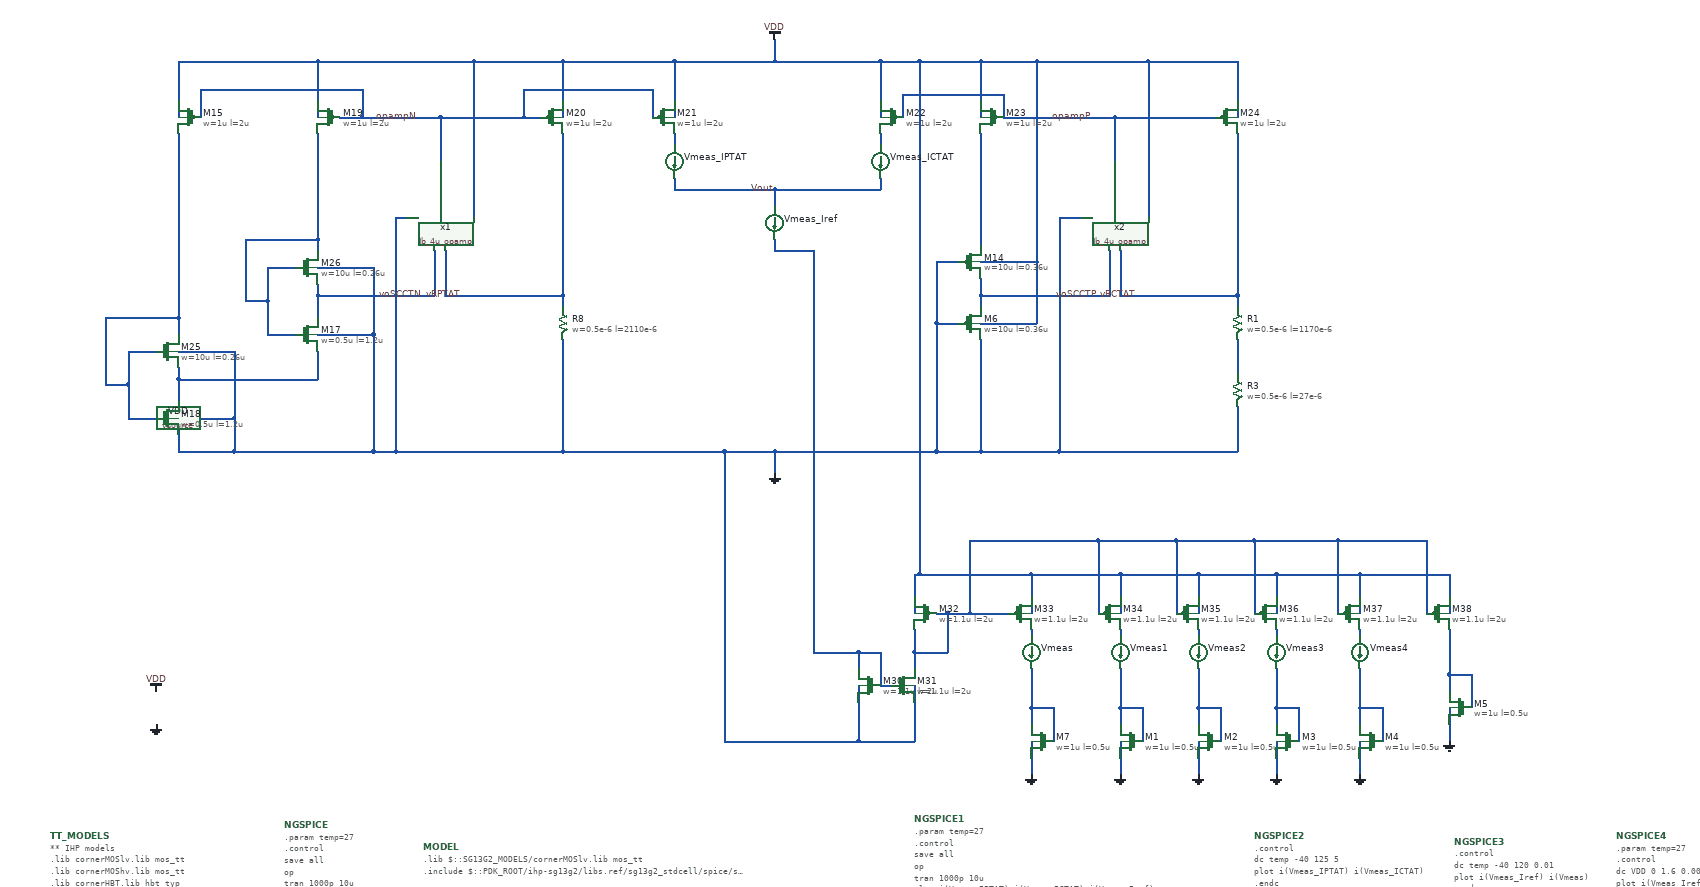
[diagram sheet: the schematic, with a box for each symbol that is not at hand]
v {xschem version=3.4.6 file_version=1.2}
G {}
K {}
V {}
S {}
E {}
N 1470 -410 1470 -310 {lab=GND}
N 1470 -470 1470 -440 {lab=#net1}
N 1510 -410 1530 -410 {lab=#net1}
N 1510 -470 1510 -410 {lab=#net1}
N 1570 -470 1570 -440 {lab=#net2}
N 1470 -310 1570 -310 {lab=GND}
N 1780 -610 1940 -610 {lab=VDD}
N 1570 -610 1570 -540 {lab=VDD}
N 1670 -540 1740 -540 {lab=#net2}
N 1940 -610 1940 -540 {lab=VDD}
N 2080 -610 2080 -540 {lab=VDD}
N 1940 -610 2080 -610 {lab=VDD}
N 2220 -610 2220 -540 {lab=VDD}
N 2080 -610 2220 -610 {lab=VDD}
N 2370 -610 2370 -540 {lab=VDD}
N 2220 -610 2370 -610 {lab=VDD}
N 2530 -610 2530 -540 {lab=VDD}
N 2370 -610 2530 -610 {lab=VDD}
N 1570 -410 1570 -310 {lab=GND}
N 1670 -670 1670 -540 {lab=#net2}
N 1630 -540 1670 -540 {lab=#net2}
N 1780 -610 1780 -540 {lab=VDD}
N 1580 -610 1780 -610 {lab=VDD}
N 2490 -670 2490 -540 {lab=#net2}
N 2330 -670 2490 -670 {lab=#net2}
N 2330 -670 2330 -540 {lab=#net2}
N 2180 -670 2330 -670 {lab=#net2}
N 2180 -670 2180 -540 {lab=#net2}
N 2040 -670 2180 -670 {lab=#net2}
N 2040 -670 2040 -540 {lab=#net2}
N 1900 -670 2040 -670 {lab=#net2}
N 1900 -670 1900 -540 {lab=#net2}
N 1670 -670 1900 -670 {lab=#net2}
N 1570 -470 1630 -470 {lab=#net2}
N 1570 -510 1570 -470 {lab=#net2}
N 1630 -540 1630 -470 {lab=#net2}
N 1610 -540 1630 -540 {lab=#net2}
N 1780 -510 1780 -500 {lab=#net3}
N 1940 -510 1940 -500 {lab=#net4}
N 2080 -510 2080 -500 {lab=#net5}
N 2220 -510 2220 -500 {lab=#net6}
N 2370 -510 2370 -500 {lab=#net7}
N 2530 -510 2530 -430 {lab=#net8}
N 1470 -470 1510 -470 {lab=#net1}
N 1730 -1470 1730 -1430 {lab=opampP}
N 1610 -1170 1650 -1170 {lab=GND}
N 1610 -1060 1650 -1060 {lab=GND}
N 1690 -1110 1690 -1090 {lab=voSCCTP}
N 1930 -1430 1930 -1350 {lab=opampP}
N 1730 -1430 1930 -1430 {lab=opampP}
N 1140 -1530 1140 -1430 {lab=VDD}
N 1510 -1530 1510 -1430 {lab=VDD}
N 1690 -1530 1690 -1430 {lab=VDD}
N 2150 -1530 2150 -1430 {lab=VDD}
N 250 -1530 500 -1530 {lab=VDD}
N 940 -1530 940 -1430 {lab=VDD}
N 870 -1430 900 -1430 {lab=opampN}
N 870 -1480 870 -1430 {lab=opampN}
N 1100 -1480 1100 -1430 {lab=opampN}
N 1550 -1470 1550 -1430 {lab=opampP}
N 500 -1530 500 -1430 {lab=VDD}
N 720 -1430 720 -1350 {lab=opampN}
N 580 -1430 720 -1430 {lab=opampN}
N 780 -1530 940 -1530 {lab=VDD}
N 500 -1110 500 -1070 {lab=voSCCTN}
N 500 -1160 600 -1160 {lab=GND}
N 600 -1160 600 -1040 {lab=GND}
N 500 -1040 600 -1040 {lab=GND}
N 410 -1160 460 -1160 {lab=#net9}
N 410 -1100 410 -1040 {lab=#net9}
N 410 -1040 460 -1040 {lab=#net9}
N 500 -1210 500 -1190 {lab=#net9}
N 370 -1100 410 -1100 {lab=#net9}
N 410 -1160 410 -1100 {lab=#net9}
N 370 -1210 370 -1100 {lab=#net9}
N 370 -1210 500 -1210 {lab=#net9}
N 500 -1400 500 -1210 {lab=#net9}
N 500 -1110 710 -1110 {lab=voSCCTN}
N 500 -1130 500 -1110 {lab=voSCCTN}
N 710 -1190 710 -1110 {lab=voSCCTN}
N 250 -960 250 -920 {lab=#net10}
N 250 -1010 350 -1010 {lab=GND}
N 350 -1010 350 -890 {lab=GND}
N 250 -890 350 -890 {lab=GND}
N 160 -1010 210 -1010 {lab=#net11}
N 160 -950 160 -890 {lab=#net11}
N 160 -890 210 -890 {lab=#net11}
N 120 -950 160 -950 {lab=#net11}
N 160 -1010 160 -950 {lab=#net11}
N 250 -960 500 -960 {lab=#net10}
N 250 -980 250 -960 {lab=#net10}
N 500 -1010 500 -960 {lab=#net10}
N 250 -1070 250 -1040 {lab=#net11}
N 250 -1530 250 -1430 {lab=VDD}
N 290 -1480 290 -1430 {lab=opampN}
N 290 -1480 580 -1480 {lab=opampN}
N 580 -1480 580 -1430 {lab=opampN}
N 540 -1430 580 -1430 {lab=opampN}
N 250 -870 250 -830 {lab=GND}
N 120 -1070 120 -950 {lab=#net11}
N 120 -1070 250 -1070 {lab=#net11}
N 250 -1400 250 -1070 {lab=#net11}
N 1610 -1170 1610 -1060 {lab=GND}
N 1830 -830 2150 -830 {lab=GND}
N 600 -1040 600 -830 {lab=GND}
N 350 -830 600 -830 {lab=GND}
N 350 -890 350 -830 {lab=GND}
N 250 -830 350 -830 {lab=GND}
N 1690 -1060 1790 -1060 {lab=VDD}
N 940 -1110 940 -1090 {lab=vRPTAT}
N 940 -1030 940 -830 {lab=GND}
N 640 -830 940 -830 {lab=GND}
N 730 -1190 730 -1110 {lab=vRPTAT}
N 730 -1110 940 -1110 {lab=vRPTAT}
N 940 -1400 940 -1110 {lab=vRPTAT}
N 1940 -1110 2150 -1110 {lab=vRCTAT}
N 2150 -1400 2150 -1110 {lab=vRCTAT}
N 1940 -1190 1940 -1110 {lab=vRCTAT}
N 1920 -1190 1920 -1110 {lab=voSCCTP}
N 1690 -1400 1690 -1200 {lab=#net12}
N 1690 -1030 1690 -830 {lab=GND}
N 1690 -1110 1920 -1110 {lab=voSCCTP}
N 1690 -1140 1690 -1110 {lab=voSCCTP}
N 1790 -1170 1790 -1060 {lab=VDD}
N 1690 -1530 1790 -1530 {lab=VDD}
N 1830 -1250 1870 -1250 {lab=GND}
N 1830 -1250 1830 -830 {lab=GND}
N 1690 -830 1830 -830 {lab=GND}
N 1990 -1530 2150 -1530 {lab=VDD}
N 1610 -830 1690 -830 {lab=GND}
N 1610 -1060 1610 -830 {lab=GND}
N 1320 -830 1610 -830 {lab=GND}
N 1550 -1470 1730 -1470 {lab=opampP}
N 870 -1480 1100 -1480 {lab=opampN}
N 940 -1530 1140 -1530 {lab=VDD}
N 1580 -1530 1690 -1530 {lab=VDD}
N 1320 -1530 1510 -1530 {lab=VDD}
N 1320 -1570 1320 -1530 {lab=VDD}
N 1140 -1530 1320 -1530 {lab=VDD}
N 1320 -830 1320 -790 {lab=GND}
N 1230 -830 1320 -830 {lab=GND}
N 640 -1250 660 -1250 {lab=GND}
N 640 -1250 640 -830 {lab=GND}
N 600 -830 640 -830 {lab=GND}
N 1690 -1170 1790 -1170 {lab=VDD}
N 1790 -1530 1790 -1170 {lab=VDD}
N 1320 -1300 1510 -1300 {lab=Vout}
N 1510 -1320 1510 -1300 {lab=Vout}
N 1140 -1320 1140 -1300 {lab=Vout}
N 1140 -1400 1140 -1380 {lab=#net13}
N 1510 -1400 1510 -1380 {lab=#net14}
N 1320 -1300 1320 -1270 {lab=Vout}
N 1140 -1300 1320 -1300 {lab=Vout}
N 1320 -1210 1320 -1190 {lab=#net1}
N 780 -1530 780 -1250 {lab=VDD}
N 500 -1530 780 -1530 {lab=VDD}
N 1990 -1530 1990 -1250 {lab=VDD}
N 1790 -1530 1990 -1530 {lab=VDD}
N 720 -1430 870 -1430 {lab=opampN}
N 1930 -1430 2110 -1430 {lab=opampP}
N 1320 -1190 1390 -1190 {lab=#net1}
N 1390 -1190 1390 -470 {lab=#net1}
N 1390 -470 1470 -470 {lab=#net1}
N 1230 -310 1470 -310 {lab=GND}
N 1230 -830 1230 -310 {lab=GND}
N 940 -830 1230 -830 {lab=GND}
N 1510 -1530 1580 -1530 {lab=VDD}
N 1580 -1530 1580 -610 {lab=VDD}
N 1570 -610 1580 -610 {lab=VDD}
N 2150 -1030 2150 -970 {lab=#net15}
N 2150 -910 2150 -830 {lab=GND}
N 1780 -370 1780 -340 {lab=#net16}
N 1820 -370 1820 -310 {lab=#net16}
N 1780 -370 1820 -370 {lab=#net16}
N 1780 -310 1780 -250 {lab=GND}
N 1780 -440 1780 -370 {lab=#net16}
N 1940 -370 1940 -340 {lab=#net17}
N 1980 -370 1980 -310 {lab=#net17}
N 1940 -370 1980 -370 {lab=#net17}
N 1940 -310 1940 -250 {lab=GND}
N 1940 -440 1940 -370 {lab=#net17}
N 2080 -370 2080 -340 {lab=#net18}
N 2120 -370 2120 -310 {lab=#net18}
N 2080 -370 2120 -370 {lab=#net18}
N 2080 -310 2080 -250 {lab=GND}
N 2080 -440 2080 -370 {lab=#net18}
N 2220 -370 2220 -340 {lab=#net19}
N 2260 -370 2260 -310 {lab=#net19}
N 2220 -370 2260 -370 {lab=#net19}
N 2220 -310 2220 -250 {lab=GND}
N 2220 -440 2220 -370 {lab=#net19}
N 2370 -370 2370 -340 {lab=#net20}
N 2410 -370 2410 -310 {lab=#net20}
N 2370 -370 2410 -370 {lab=#net20}
N 2370 -310 2370 -250 {lab=GND}
N 2370 -440 2370 -370 {lab=#net20}
N 2530 -430 2530 -400 {lab=#net8}
N 2570 -430 2570 -370 {lab=#net8}
N 2530 -430 2570 -430 {lab=#net8}
N 2530 -370 2530 -310 {lab=GND}
N 2150 -1110 2150 -1090 {lab=vRCTAT}
C {vsource.sym} 210 -370 0 0 {name=VDD value=1 savecurrent=false}
C {vdd.sym} 210 -400 0 0 {name=l1 lab=VDD}
C {gnd.sym} 210 -340 0 0 {name=l3 lab=GND}
C {sg13g2_pr/sg13_lv_nmos.sym} 1490 -410 0 1 {name=M30
l=2u
w=1.1u
ng=1
m=3
model=sg13_lv_nmos
spiceprefix=X
}
C {sg13g2_pr/sg13_lv_nmos.sym} 1550 -410 0 0 {name=M31
l=2u
w=1.1u
ng=1
m=3
model=sg13_lv_nmos
spiceprefix=X
}
C {sg13g2_pr/sg13_lv_pmos.sym} 1590 -540 0 1 {name=M32
l=2u
w=1.1u
ng=1
m=6
model=sg13_lv_pmos
spiceprefix=X
}
C {sg13g2_pr/sg13_lv_pmos.sym} 1760 -540 0 0 {name=M33
l=2u
w=1.1u
ng=1
m=6
model=sg13_lv_pmos
spiceprefix=X
}
C {sg13g2_pr/sg13_lv_pmos.sym} 1920 -540 0 0 {name=M34
l=2u
w=1.1u
ng=1
m=6
model=sg13_lv_pmos
spiceprefix=X
}
C {sg13g2_pr/sg13_lv_pmos.sym} 2060 -540 0 0 {name=M35
l=2u
w=1.1u
ng=1
m=6
model=sg13_lv_pmos
spiceprefix=X
}
C {sg13g2_pr/sg13_lv_pmos.sym} 2200 -540 0 0 {name=M36
l=2u
w=1.1u
ng=1
m=6
model=sg13_lv_pmos
spiceprefix=X
}
C {sg13g2_pr/sg13_lv_pmos.sym} 2350 -540 0 0 {name=M37
l=2u
w=1.1u
ng=1
m=6
model=sg13_lv_pmos
spiceprefix=X
}
C {sg13g2_pr/sg13_lv_pmos.sym} 2510 -540 0 0 {name=M38
l=2u
w=1.1u
ng=1
m=6
model=sg13_lv_pmos
spiceprefix=X
}
C {ammeter.sym} 1780 -470 0 0 {name=Vmeas savecurrent=true spice_ignore=0}
C {ammeter.sym} 1940 -470 0 0 {name=Vmeas1 savecurrent=true spice_ignore=0}
C {ammeter.sym} 2080 -470 0 0 {name=Vmeas2 savecurrent=true spice_ignore=0}
C {ammeter.sym} 2220 -470 0 0 {name=Vmeas3 savecurrent=true spice_ignore=0}
C {ammeter.sym} 2370 -470 0 0 {name=Vmeas4 savecurrent=true spice_ignore=0}
C {code_shown.sym} 20 -140 0 0 {
name=TT_MODELS
only_toplevel=true
value="
** IHP models
.lib cornerMOSlv.lib mos_tt
.lib cornerMOShv.lib mos_tt
.lib cornerHBT.lib hbt_typ
.lib cornerRES.lib res_typ
"
spice_ignore=false
      }
C {devices/code_shown.sym} 440 -160 0 0 {name=NGSPICE only_toplevel=true
value="
.param temp=27
.control
save all
op
tran 1000p 10u
plot v(voSCCTP) v(vRPTAT) v(voSCCTN) v(vRCTAT) v(opampN) v(opampP) 
.endc
"


}
C {devices/code_shown.sym} 690 -120 0 0 {name=MODEL
only_toplevel=true
format="tcleval( @value )"
value="
.lib $::SG13G2_MODELS/cornerMOSlv.lib mos_tt
.include $::PDK_ROOT/ihp-sg13g2/libs.ref/sg13g2_stdcell/spice/sg13g2_stdcell.spice
"
place=header}
C {devices/code_shown.sym} 1570 -170 0 0 {name=NGSPICE1 only_toplevel=true
value="
.param temp=27
.control
save all
op
tran 1000p 10u
plot i(Vmeas_IPTAT) i(Vmeas_ICTAT) i(Vmeas_Iref)
.endc
"


}
C {devices/code_shown.sym} 2180 -140 0 0 {name=NGSPICE2 only_toplevel=true
value="
.control 
dc temp -40 125 5
plot i(Vmeas_IPTAT) i(Vmeas_ICTAT)
.endc
"


}
C {devices/code_shown.sym} 2540 -130 0 0 {name=NGSPICE3 only_toplevel=true
value="
.control 
dc temp -40 120 0.01
plot i(Vmeas_Iref) i(Vmeas)
.endc
"


}
C {devices/code_shown.sym} 2830 -140 0 0 {name=NGSPICE4 only_toplevel=true
value="
.param temp=27
.control
dc VDD 0 1.6 0.0001
plot i(Vmeas_Iref)
.endc 
"


}
C {vdd.sym} 1320 -1570 0 0 {name=l11 lab=VDD}
C {lab_pin.sym} 1320 -1300 3 1 {name=p1 sig_type=std_logic lab=Vout}
C {sg13g2_pr/sg13_lv_nmos.sym} 480 -1040 0 0 {name=M17
l=1.2u
w=0.5u
ng=1
m=1
model=sg13_lv_nmos
spiceprefix=X
}
C {sg13g2_pr/sg13_lv_pmos.sym} 270 -1430 0 1 {name=M15
l=2u
w=1u
ng=1
m=1
model=sg13_lv_pmos
spiceprefix=X
}
C {sg13g2_pr/sg13_lv_nmos.sym} 230 -890 0 0 {name=M18
l=1.2u
w=0.5u
ng=1
m=1
model=sg13_lv_nmos
spiceprefix=X
}
C {gnd.sym} 1320 -790 0 0 {name=l13 lab=GND}
C {lab_pin.sym} 1900 -1110 3 0 {name=p2 sig_type=std_logic lab=voSCCTP}
C {lab_pin.sym} 690 -1110 3 0 {name=p3 sig_type=std_logic lab=voSCCTN}
C {lab_pin.sym} 1970 -1110 3 0 {name=p6 sig_type=std_logic lab=vRCTAT}
C {lab_pin.sym} 760 -1110 3 0 {name=p7 sig_type=std_logic lab=vRPTAT}
C {ammeter.sym} 1140 -1350 0 0 {name=Vmeas_IPTAT savecurrent=true spice_ignore=0}
C {ammeter.sym} 1510 -1350 0 0 {name=Vmeas_ICTAT savecurrent=true spice_ignore=0}
C {ammeter.sym} 1320 -1240 0 0 {name=Vmeas_Iref savecurrent=true spice_ignore=0}
C {sg13g2_pr/sg13_lv_pmos.sym} 520 -1430 0 1 {name=M19
l=2u
w=1u
ng=1
m=1
model=sg13_lv_pmos
spiceprefix=X
}
C {sg13g2_pr/sg13_lv_pmos.sym} 920 -1430 0 0 {name=M20
l=2u
w=1u
ng=1
m=1
model=sg13_lv_pmos
spiceprefix=X
}
C {sg13g2_pr/sg13_lv_pmos.sym} 1120 -1430 0 0 {name=M21
l=2u
w=1u
ng=1
m=6
model=sg13_lv_pmos
spiceprefix=X
}
C {sg13g2_pr/sg13_lv_pmos.sym} 1530 -1430 0 1 {name=M22
l=2u
w=1u
ng=1
m=6
model=sg13_lv_pmos
spiceprefix=X
}
C {sg13g2_pr/sg13_lv_pmos.sym} 1710 -1430 0 1 {name=M23
l=2u
w=1u
ng=1
m=1
model=sg13_lv_pmos
spiceprefix=X
}
C {sg13g2_pr/sg13_lv_pmos.sym} 2130 -1430 0 0 {name=M24
l=2u
w=1u
ng=1
m=1
model=sg13_lv_pmos
spiceprefix=X
}
C {lab_pin.sym} 1890 -1430 1 0 {name=p8 sig_type=std_logic lab=opampP}
C {lab_pin.sym} 680 -1430 1 0 {name=p13 sig_type=std_logic lab=opampN}
C {sg13g2_pr/sg13_lv_nmos.sym} 230 -1010 0 0 {name=M25
l=0.26u
w=10u
ng=1
m=30
model=sg13_lv_nmos
spiceprefix=X
}
C {sg13g2_pr/sg13_lv_nmos.sym} 480 -1160 0 0 {name=M26
l=0.26u
w=10u
ng=1
m=30
model=sg13_lv_nmos
spiceprefix=X
}
C {sg13g2_pr/rppd.sym} 940 -1060 0 0 {name=R8
w=0.5e-6
l=2110e-6
model=rppd
body=GND
spiceprefix=X
b=0
m=1
}
C {sg13g2_pr/rppd.sym} 2150 -1060 0 0 {name=R1
w=0.5e-6
l=1170e-6
model=rppd
body=GND
spiceprefix=X
b=0
m=1
}
C {sg13g2_pr/rhigh.sym} 2150 -940 0 0 {name=R3
w=0.5e-6
l=27e-6
model=rhigh
body=GND
spiceprefix=X
b=0
m=1
}
C {sg13g2_pr/sg13_lv_nmos.sym} 1800 -310 0 1 {name=M7
l=0.5u
w=1u
ng=1
m=1
model=sg13_lv_nmos
spiceprefix=X
}
C {gnd.sym} 1780 -250 0 0 {name=l9 lab=GND}
C {sg13g2_pr/sg13_lv_nmos.sym} 1960 -310 0 1 {name=M1
l=0.5u
w=1u
ng=1
m=1
model=sg13_lv_nmos
spiceprefix=X
}
C {gnd.sym} 1940 -250 0 0 {name=l10 lab=GND}
C {sg13g2_pr/sg13_lv_nmos.sym} 2100 -310 0 1 {name=M2
l=0.5u
w=1u
ng=1
m=1
model=sg13_lv_nmos
spiceprefix=X
}
C {gnd.sym} 2080 -250 0 0 {name=l12 lab=GND}
C {sg13g2_pr/sg13_lv_nmos.sym} 2240 -310 0 1 {name=M3
l=0.5u
w=1u
ng=1
m=1
model=sg13_lv_nmos
spiceprefix=X
}
C {gnd.sym} 2220 -250 0 0 {name=l14 lab=GND}
C {sg13g2_pr/sg13_lv_nmos.sym} 2390 -310 0 1 {name=M4
l=0.5u
w=1u
ng=1
m=1
model=sg13_lv_nmos
spiceprefix=X
}
C {gnd.sym} 2370 -250 0 0 {name=l15 lab=GND}
C {sg13g2_pr/sg13_lv_nmos.sym} 2550 -370 0 1 {name=M5
l=0.5u
w=1u
ng=1
m=1
model=sg13_lv_nmos
spiceprefix=X
}
C {gnd.sym} 2530 -310 0 0 {name=l16 lab=GND}
C {sg13g2_pr/sg13_lv_pmos.sym} 1670 -1060 0 0 {name=M6
l=0.36u
w=10u
ng=1
m=20
model=sg13_lv_pmos
spiceprefix=X
}
C {sg13g2_pr/sg13_lv_pmos.sym} 1670 -1170 0 0 {name=M14
l=0.36u
w=10u
ng=1
m=1
model=sg13_lv_pmos
spiceprefix=X
}
C {/shared/designs/SSDOR_w_startup_1V_ihp/Ib_4u/Ib_4u_opamp/Ib_4u_opamp.sym} 1870 -1190 1 1 {name=x2}
C {/shared/designs/SSDOR_w_startup_1V_ihp/Ib_4u/Ib_4u_opamp/Ib_4u_opamp.sym} 660 -1190 1 1 {name=x1}
